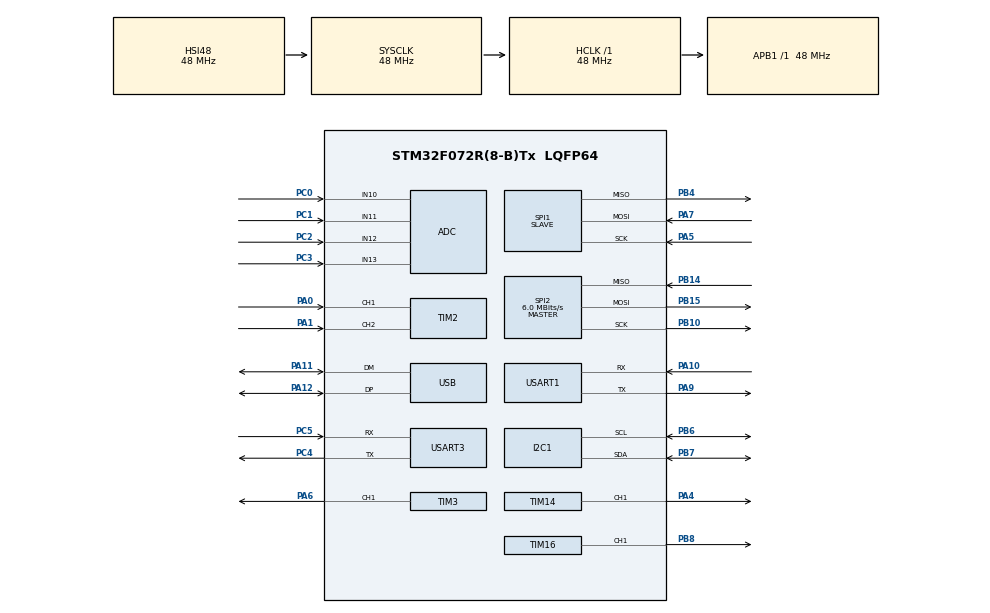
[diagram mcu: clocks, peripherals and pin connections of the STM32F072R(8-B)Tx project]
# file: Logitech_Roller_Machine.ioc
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Dma.I2C1_RX.4.Direction=DMA_PERIPH_TO_MEMORY
Dma.I2C1_RX.4.Instance=DMA1_Channel3
Dma.I2C1_RX.4.MemDataAlignment=DMA_MDATAALIGN_BYTE
Dma.I2C1_RX.4.MemInc=DMA_MINC_ENABLE
Dma.I2C1_RX.4.Mode=DMA_NORMAL
Dma.I2C1_RX.4.PeriphDataAlignment=DMA_PDATAALIGN_BYTE
Dma.I2C1_RX.4.PeriphInc=DMA_PINC_DISABLE
Dma.I2C1_RX.4.Priority=DMA_PRIORITY_LOW
Dma.I2C1_TX.5.Direction=DMA_MEMORY_TO_PERIPH
Dma.I2C1_TX.5.Instance=DMA1_Channel2
Dma.I2C1_TX.5.MemDataAlignment=DMA_MDATAALIGN_BYTE
Dma.I2C1_TX.5.MemInc=DMA_MINC_ENABLE
Dma.I2C1_TX.5.Mode=DMA_NORMAL
Dma.I2C1_TX.5.PeriphDataAlignment=DMA_PDATAALIGN_BYTE
Dma.I2C1_TX.5.PeriphInc=DMA_PINC_DISABLE
Dma.I2C1_TX.5.Priority=DMA_PRIORITY_LOW
Dma.Request0=USART3_RX
Dma.Request1=USART3_TX
Dma.Request2=USART1_RX
Dma.Request3=USART1_TX
Dma.Request4=I2C1_RX
Dma.Request5=I2C1_TX
Dma.USART1_RX.2.Direction=DMA_PERIPH_TO_MEMORY
Dma.USART1_RX.2.Instance=DMA1_Channel5
Dma.USART1_RX.2.MemDataAlignment=DMA_MDATAALIGN_BYTE
Dma.USART1_RX.2.MemInc=DMA_MINC_ENABLE
Dma.USART1_RX.2.Mode=DMA_NORMAL
Dma.USART1_RX.2.PeriphDataAlignment=DMA_PDATAALIGN_BYTE
Dma.USART1_RX.2.PeriphInc=DMA_PINC_DISABLE
Dma.USART1_RX.2.Priority=DMA_PRIORITY_LOW
Dma.USART1_TX.3.Direction=DMA_MEMORY_TO_PERIPH
Dma.USART1_TX.3.Instance=DMA1_Channel4
Dma.USART1_TX.3.MemDataAlignment=DMA_MDATAALIGN_BYTE
Dma.USART1_TX.3.MemInc=DMA_MINC_ENABLE
Dma.USART1_TX.3.Mode=DMA_NORMAL
Dma.USART1_TX.3.PeriphDataAlignment=DMA_PDATAALIGN_BYTE
Dma.USART1_TX.3.PeriphInc=DMA_PINC_DISABLE
Dma.USART1_TX.3.Priority=DMA_PRIORITY_LOW
Dma.USART3_RX.0.Direction=DMA_PERIPH_TO_MEMORY
Dma.USART3_RX.0.Instance=DMA1_Channel6
Dma.USART3_RX.0.MemDataAlignment=DMA_MDATAALIGN_BYTE
Dma.USART3_RX.0.MemInc=DMA_MINC_ENABLE
Dma.USART3_RX.0.Mode=DMA_NORMAL
Dma.USART3_RX.0.PeriphDataAlignment=DMA_PDATAALIGN_BYTE
Dma.USART3_RX.0.PeriphInc=DMA_PINC_DISABLE
Dma.USART3_RX.0.Priority=DMA_PRIORITY_LOW
Dma.USART3_TX.1.Direction=DMA_MEMORY_TO_PERIPH
Dma.USART3_TX.1.Instance=DMA1_Channel7
Dma.USART3_TX.1.MemDataAlignment=DMA_MDATAALIGN_BYTE
Dma.USART3_TX.1.MemInc=DMA_MINC_ENABLE
Dma.USART3_TX.1.Mode=DMA_NORMAL
Dma.USART3_TX.1.PeriphDataAlignment=DMA_PDATAALIGN_BYTE
Dma.USART3_TX.1.PeriphInc=DMA_PINC_DISABLE
Dma.USART3_TX.1.Priority=DMA_PRIORITY_LOW
Mcu.Family=STM32F0
Mcu.Name=STM32F072R(8-B)Tx
Mcu.Package=LQFP64
NVIC.DMA1_Channel2_3_IRQn=true\:0\:0\:false\:false\:true\:false\:true
NVIC.DMA1_Channel4_5_6_7_IRQn=true\:0\:0\:false\:false\:true\:false\:true
PA0.Signal=S_TIM2_CH1_ETR
PA1.Signal=S_TIM2_CH2
PA10.Mode=Asynchronous
PA10.Signal=USART1_RX
PA11.Mode=Device
PA11.Signal=USB_DM
PA12.Mode=Device
PA12.Signal=USB_DP
PA4.Signal=S_TIM14_CH1
PA5.Mode=Full_Duplex_Slave
PA5.Signal=SPI1_SCK
PA6.Signal=S_TIM3_CH1
PA7.Mode=Full_Duplex_Slave
PA7.Signal=SPI1_MOSI
PA9.Mode=Asynchronous
PA9.Signal=USART1_TX
PB10.Mode=Full_Duplex_Master
PB10.Signal=SPI2_SCK
PB14.Mode=Full_Duplex_Master
PB14.Signal=SPI2_MISO
PB15.Mode=Full_Duplex_Master
PB15.Signal=SPI2_MOSI
PB4.Mode=Full_Duplex_Slave
PB4.Signal=SPI1_MISO
PB6.Mode=I2C
PB6.Signal=I2C1_SCL
PB7.Mode=I2C
PB7.Signal=I2C1_SDA
PB8.Signal=S_TIM16_CH1
PC0.Mode=IN10
PC0.Signal=ADC_IN10
PC1.Mode=IN11
PC1.Signal=ADC_IN11
PC2.Mode=IN12
PC2.Signal=ADC_IN12
PC3.Mode=IN13
PC3.Signal=ADC_IN13
PC4.Mode=Asynchronous
PC4.Signal=USART3_TX
PC5.Mode=Asynchronous
PC5.Signal=USART3_RX
ProjectManager.HeapSize=0x200
ProjectManager.StackSize=0x400
ProjectManager.TargetToolchain=MDK-ARM V5
RCC.AHBFreq_Value=48000000
RCC.APB1Freq_Value=48000000
RCC.APB1TimFreq_Value=48000000
RCC.HCLKFreq_Value=48000000
RCC.SYSCLKFreq_VALUE=48000000
RCC.SYSCLKSource=RCC_SYSCLKSOURCE_HSI48
SH.S_TIM14_CH1.0=TIM14_CH1,PWM Generation1 CH1
SH.S_TIM16_CH1.0=TIM16_CH1,PWM Generation1 CH1
SH.S_TIM2_CH1_ETR.0=TIM2_CH1,Encoder_Interface
SH.S_TIM2_CH2.0=TIM2_CH2,Encoder_Interface
SH.S_TIM3_CH1.0=TIM3_CH1,PWM Generation1 CH1
SPI1.Direction=SPI_DIRECTION_2LINES
SPI1.Mode=SPI_MODE_SLAVE
SPI1.VirtualType=VM_SLAVE
SPI2.BaudRatePrescaler=SPI_BAUDRATEPRESCALER_8
SPI2.CalculateBaudRate=6.0 MBits/s
SPI2.Direction=SPI_DIRECTION_2LINES
SPI2.Mode=SPI_MODE_MASTER
SPI2.VirtualType=VM_MASTER
TIM14.Channel=TIM_CHANNEL_1
TIM16.Channel=TIM_CHANNEL_1
TIM3.Channel-PWM\ Generation1\ CH1=TIM_CHANNEL_1
USART1.VirtualMode-Asynchronous=VM_ASYNC
USART3.VirtualMode-Asynchronous=VM_ASYNC
VP_TIM14_VS_ClockSourceINT.Mode=Enable_Timer
VP_TIM16_VS_ClockSourceINT.Mode=Enable_Timer
VP_TIM16_VS_OPM.Mode=OPM_bit
board=custom

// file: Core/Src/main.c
/* USER CODE BEGIN Header */
/**
  ******************************************************************************
  * @file           : main.c
  * @brief          : Main program body
  ******************************************************************************
  * @attention
  *
  * <h2><center>&copy; Copyright (c) 2024 STMicroelectronics.
  * All rights reserved.</center></h2>
  *
  * This software component is licensed by ST under BSD 3-Clause license,
  * the "License"; You may not use this file except in compliance with the
  * License. You may obtain a copy of the License at:
  *                        opensource.org/licenses/BSD-3-Clause
  *
  ******************************************************************************
  */
/* USER CODE END Header */
#include "main.h"
#include "motor.h"
#include "uart.h"
#include "hmi.h"

ADC_HandleTypeDef hadc;

I2C_HandleTypeDef hi2c1;
DMA_HandleTypeDef hdma_i2c1_rx;
DMA_HandleTypeDef hdma_i2c1_tx;

SPI_HandleTypeDef hspi1;
SPI_HandleTypeDef hspi2;

TIM_HandleTypeDef htim2;
TIM_HandleTypeDef htim3;
TIM_HandleTypeDef htim14;
TIM_HandleTypeDef htim16;

UART_HandleTypeDef huart1;
UART_HandleTypeDef huart3;
DMA_HandleTypeDef hdma_usart1_rx;
DMA_HandleTypeDef hdma_usart1_tx;
DMA_HandleTypeDef hdma_usart3_rx;
DMA_HandleTypeDef hdma_usart3_tx;

PCD_HandleTypeDef hpcd_USB_FS;

/* USER CODE BEGIN PV */
GPIO_FUNCTION_STRUCT wheel_motor_enable = {GPIOB, GPIO_PIN_0};
GPIO_FUNCTION_STRUCT wheel_motor_direction = {GPIOB, GPIO_PIN_1};
DC_MOTOR wheel_motor = {&wheel_motor_enable, &wheel_motor_direction, TIM14, 1, 0, 0, MOTOR_IDLE, 0, 0, 0};

uint32_t new_tick = 0;
uint32_t lastTimeTick_wheel_motor_pid = 0;
uint32_t lastTimeTick_for_test = 0;

uint16_t Target = 1280;
uint16_t _last_Target = 1280;
uint16_t _Target = 0;
int16_t encoder_value = 0;
int32_t error = 0;
int32_t ierror = 0;

int page_index = 0;
/* USER CODE END PV */

void SystemClock_Config(void);
static void MX_GPIO_Init(void);
static void MX_DMA_Init(void);
static void MX_ADC_Init(void);
static void MX_I2C1_Init(void);
static void MX_TIM2_Init(void);
static void MX_TIM3_Init(void);
static void MX_TIM14_Init(void);
static void MX_TIM16_Init(void);
static void MX_USART1_UART_Init(void);
static void MX_USART3_UART_Init(void);
static void MX_SPI1_Init(void);
static void MX_SPI2_Init(void);
static void MX_USB_PCD_Init(void);
/* USER CODE BEGIN PFP */
_Bool isElapsedTimeNoReset(uint32_t _TimeInterval ,uint32_t _lastTimeTick);
void control_wheel_position(int32_t target, int32_t PV, double P_Gain, double I_Gain, double D_Gain);
/* USER CODE END PFP */

int main(void)
{

  /* MCU Configuration--------------------------------------------------------*/

  /* Reset of all peripherals, Initializes the Flash interface and the Systick. */
  HAL_Init();

  /* Configure the system clock */
  SystemClock_Config();

  /* Initialize all configured peripherals */
  MX_GPIO_Init();
  MX_DMA_Init();
  MX_ADC_Init();
  MX_I2C1_Init();
  MX_TIM2_Init();
  MX_TIM3_Init();
  MX_TIM14_Init();
  MX_TIM16_Init();
  MX_USART1_UART_Init();
  MX_USART3_UART_Init();
  MX_SPI1_Init();
  MX_SPI2_Init();
  MX_USB_PCD_Init();
  /* USER CODE BEGIN 2 */
	//init_dc_motor(&wheel_motor);
	MSG_InitializeQeueue();
	USART1_START_RX();
	USART3_START_RX();

	WritePage_to_HMI(PAGE_INIT);
	HAL_Delay(2000);
	WritePage_to_HMI(PAGE_MAIN);

	HAL_TIM_PWM_Start(&htim14, TIM_CHANNEL_1);
	HAL_TIM_Encoder_Start(&htim2, TIM_CHANNEL_ALL);
	HAL_Delay(500);
	run_motor_pwm(&wheel_motor, 0);
	lastTimeTick_for_test = new_tick;
  /* USER CODE END 2 */

  /* Infinite loop */
  while (1)
  {
		new_tick = HAL_GetTick();

		control_wheel_position(232, TIM2->CNT, 0.35, 0.002, 6);
		//Write_Parameters_To_HMI(VALUE_MOVEMENT, TIM2->CNT);
    HAL_Delay(1);
  }
}

void SystemClock_Config(void)
{
  RCC_OscInitTypeDef RCC_OscInitStruct = {0};
  RCC_ClkInitTypeDef RCC_ClkInitStruct = {0};
  RCC_PeriphCLKInitTypeDef PeriphClkInit = {0};

  /** Initializes the RCC Oscillators according to the specified parameters
  * in the RCC_OscInitTypeDef structure.
  */
  RCC_OscInitStruct.OscillatorType = RCC_OSCILLATORTYPE_HSI|RCC_OSCILLATORTYPE_HSI14
                              |RCC_OSCILLATORTYPE_HSI48;
  RCC_OscInitStruct.HSIState = RCC_HSI_ON;
  RCC_OscInitStruct.HSI48State = RCC_HSI48_ON;
  RCC_OscInitStruct.HSI14State = RCC_HSI14_ON;
  RCC_OscInitStruct.HSICalibrationValue = RCC_HSICALIBRATION_DEFAULT;
  RCC_OscInitStruct.HSI14CalibrationValue = 16;
  RCC_OscInitStruct.PLL.PLLState = RCC_PLL_NONE;
  if (HAL_RCC_OscConfig(&RCC_OscInitStruct) != HAL_OK)
  {
    Error_Handler();
  }
  /** Initializes the CPU, AHB and APB buses clocks
  */
  RCC_ClkInitStruct.ClockType = RCC_CLOCKTYPE_HCLK|RCC_CLOCKTYPE_SYSCLK
                              |RCC_CLOCKTYPE_PCLK1;
  RCC_ClkInitStruct.SYSCLKSource = RCC_SYSCLKSOURCE_HSI48;
  RCC_ClkInitStruct.AHBCLKDivider = RCC_SYSCLK_DIV1;
  RCC_ClkInitStruct.APB1CLKDivider = RCC_HCLK_DIV1;

  if (HAL_RCC_ClockConfig(&RCC_ClkInitStruct, FLASH_LATENCY_1) != HAL_OK)
  {
    Error_Handler();
  }
  PeriphClkInit.PeriphClockSelection = RCC_PERIPHCLK_USB|RCC_PERIPHCLK_USART1
                              |RCC_PERIPHCLK_I2C1;
  PeriphClkInit.Usart1ClockSelection = RCC_USART1CLKSOURCE_PCLK1;
  PeriphClkInit.I2c1ClockSelection = RCC_I2C1CLKSOURCE_HSI;
  PeriphClkInit.UsbClockSelection = RCC_USBCLKSOURCE_HSI48;

  if (HAL_RCCEx_PeriphCLKConfig(&PeriphClkInit) != HAL_OK)
  {
    Error_Handler();
  }
}

static void MX_ADC_Init(void)
{

  ADC_ChannelConfTypeDef sConfig = {0};

  /** Configure the global features of the ADC (Clock, Resolution, Data Alignment and number of conversion)
  */
  hadc.Instance = ADC1;
  hadc.Init.ClockPrescaler = ADC_CLOCK_ASYNC_DIV1;
  hadc.Init.Resolution = ADC_RESOLUTION_12B;
  hadc.Init.DataAlign = ADC_DATAALIGN_RIGHT;
  hadc.Init.ScanConvMode = ADC_SCAN_DIRECTION_FORWARD;
  hadc.Init.EOCSelection = ADC_EOC_SINGLE_CONV;
  hadc.Init.LowPowerAutoWait = DISABLE;
  hadc.Init.LowPowerAutoPowerOff = DISABLE;
  hadc.Init.ContinuousConvMode = DISABLE;
  hadc.Init.DiscontinuousConvMode = DISABLE;
  hadc.Init.ExternalTrigConv = ADC_SOFTWARE_START;
  hadc.Init.ExternalTrigConvEdge = ADC_EXTERNALTRIGCONVEDGE_NONE;
  hadc.Init.DMAContinuousRequests = DISABLE;
  hadc.Init.Overrun = ADC_OVR_DATA_PRESERVED;
  if (HAL_ADC_Init(&hadc) != HAL_OK)
  {
    Error_Handler();
  }
  /** Configure for the selected ADC regular channel to be converted.
  */
  sConfig.Channel = ADC_CHANNEL_10;
  sConfig.Rank = ADC_RANK_CHANNEL_NUMBER;
  sConfig.SamplingTime = ADC_SAMPLETIME_1CYCLE_5;
  if (HAL_ADC_ConfigChannel(&hadc, &sConfig) != HAL_OK)
  {
    Error_Handler();
  }
  /** Configure for the selected ADC regular channel to be converted.
  */
  sConfig.Channel = ADC_CHANNEL_11;
  if (HAL_ADC_ConfigChannel(&hadc, &sConfig) != HAL_OK)
  {
    Error_Handler();
  }
  /** Configure for the selected ADC regular channel to be converted.
  */
  sConfig.Channel = ADC_CHANNEL_12;
  if (HAL_ADC_ConfigChannel(&hadc, &sConfig) != HAL_OK)
  {
    Error_Handler();
  }
  /** Configure for the selected ADC regular channel to be converted.
  */
  sConfig.Channel = ADC_CHANNEL_13;
  if (HAL_ADC_ConfigChannel(&hadc, &sConfig) != HAL_OK)
  {
    Error_Handler();
  }

}

static void MX_I2C1_Init(void)
{

  hi2c1.Instance = I2C1;
  hi2c1.Init.Timing = 0x2000090E;
  hi2c1.Init.OwnAddress1 = 0;
  hi2c1.Init.AddressingMode = I2C_ADDRESSINGMODE_7BIT;
  hi2c1.Init.DualAddressMode = I2C_DUALADDRESS_DISABLE;
  hi2c1.Init.OwnAddress2 = 0;
  hi2c1.Init.OwnAddress2Masks = I2C_OA2_NOMASK;
  hi2c1.Init.GeneralCallMode = I2C_GENERALCALL_DISABLE;
  hi2c1.Init.NoStretchMode = I2C_NOSTRETCH_DISABLE;
  if (HAL_I2C_Init(&hi2c1) != HAL_OK)
  {
    Error_Handler();
  }
  /** Configure Analogue filter
  */
  if (HAL_I2CEx_ConfigAnalogFilter(&hi2c1, I2C_ANALOGFILTER_ENABLE) != HAL_OK)
  {
    Error_Handler();
  }
  /** Configure Digital filter
  */
  if (HAL_I2CEx_ConfigDigitalFilter(&hi2c1, 0) != HAL_OK)
  {
    Error_Handler();
  }

}

static void MX_SPI1_Init(void)
{

  /* SPI1 parameter configuration*/
  hspi1.Instance = SPI1;
  hspi1.Init.Mode = SPI_MODE_SLAVE;
  hspi1.Init.Direction = SPI_DIRECTION_2LINES;
  hspi1.Init.DataSize = SPI_DATASIZE_4BIT;
  hspi1.Init.CLKPolarity = SPI_POLARITY_LOW;
  hspi1.Init.CLKPhase = SPI_PHASE_1EDGE;
  hspi1.Init.NSS = SPI_NSS_SOFT;
  hspi1.Init.FirstBit = SPI_FIRSTBIT_MSB;
  hspi1.Init.TIMode = SPI_TIMODE_DISABLE;
  hspi1.Init.CRCCalculation = SPI_CRCCALCULATION_DISABLE;
  hspi1.Init.CRCPolynomial = 7;
  hspi1.Init.CRCLength = SPI_CRC_LENGTH_DATASIZE;
  hspi1.Init.NSSPMode = SPI_NSS_PULSE_DISABLE;
  if (HAL_SPI_Init(&hspi1) != HAL_OK)
  {
    Error_Handler();
  }

}

static void MX_SPI2_Init(void)
{

  /* SPI2 parameter configuration*/
  hspi2.Instance = SPI2;
  hspi2.Init.Mode = SPI_MODE_MASTER;
  hspi2.Init.Direction = SPI_DIRECTION_2LINES;
  hspi2.Init.DataSize = SPI_DATASIZE_4BIT;
  hspi2.Init.CLKPolarity = SPI_POLARITY_LOW;
  hspi2.Init.CLKPhase = SPI_PHASE_1EDGE;
  hspi2.Init.NSS = SPI_NSS_SOFT;
  hspi2.Init.BaudRatePrescaler = SPI_BAUDRATEPRESCALER_8;
  hspi2.Init.FirstBit = SPI_FIRSTBIT_MSB;
  hspi2.Init.TIMode = SPI_TIMODE_DISABLE;
  hspi2.Init.CRCCalculation = SPI_CRCCALCULATION_DISABLE;
  hspi2.Init.CRCPolynomial = 7;
  hspi2.Init.CRCLength = SPI_CRC_LENGTH_DATASIZE;
  hspi2.Init.NSSPMode = SPI_NSS_PULSE_ENABLE;
  if (HAL_SPI_Init(&hspi2) != HAL_OK)
  {
    Error_Handler();
  }

}

static void MX_TIM2_Init(void)
{

  TIM_Encoder_InitTypeDef sConfig = {0};
  TIM_MasterConfigTypeDef sMasterConfig = {0};

  htim2.Instance = TIM2;
  htim2.Init.Prescaler = 0;
  htim2.Init.CounterMode = TIM_COUNTERMODE_UP;
  htim2.Init.Period = 4294967295;
  htim2.Init.ClockDivision = TIM_CLOCKDIVISION_DIV1;
  htim2.Init.AutoReloadPreload = TIM_AUTORELOAD_PRELOAD_DISABLE;
  sConfig.EncoderMode = TIM_ENCODERMODE_TI12;
  sConfig.IC1Polarity = TIM_ICPOLARITY_RISING;
  sConfig.IC1Selection = TIM_ICSELECTION_DIRECTTI;
  sConfig.IC1Prescaler = TIM_ICPSC_DIV1;
  sConfig.IC1Filter = 0;
  sConfig.IC2Polarity = TIM_ICPOLARITY_RISING;
  sConfig.IC2Selection = TIM_ICSELECTION_DIRECTTI;
  sConfig.IC2Prescaler = TIM_ICPSC_DIV1;
  sConfig.IC2Filter = 0;
  if (HAL_TIM_Encoder_Init(&htim2, &sConfig) != HAL_OK)
  {
    Error_Handler();
  }
  sMasterConfig.MasterOutputTrigger = TIM_TRGO_RESET;
  sMasterConfig.MasterSlaveMode = TIM_MASTERSLAVEMODE_DISABLE;
  if (HAL_TIMEx_MasterConfigSynchronization(&htim2, &sMasterConfig) != HAL_OK)
  {
    Error_Handler();
  }

}

static void MX_TIM3_Init(void)
{

  TIM_MasterConfigTypeDef sMasterConfig = {0};
  TIM_OC_InitTypeDef sConfigOC = {0};

  htim3.Instance = TIM3;
  htim3.Init.Prescaler = 0;
  htim3.Init.CounterMode = TIM_COUNTERMODE_UP;
  htim3.Init.Period = 65535;
  htim3.Init.ClockDivision = TIM_CLOCKDIVISION_DIV1;
  htim3.Init.AutoReloadPreload = TIM_AUTORELOAD_PRELOAD_DISABLE;
  if (HAL_TIM_PWM_Init(&htim3) != HAL_OK)
  {
    Error_Handler();
  }
  sMasterConfig.MasterOutputTrigger = TIM_TRGO_RESET;
  sMasterConfig.MasterSlaveMode = TIM_MASTERSLAVEMODE_DISABLE;
  if (HAL_TIMEx_MasterConfigSynchronization(&htim3, &sMasterConfig) != HAL_OK)
  {
    Error_Handler();
  }
  sConfigOC.OCMode = TIM_OCMODE_PWM1;
  sConfigOC.Pulse = 0;
  sConfigOC.OCPolarity = TIM_OCPOLARITY_HIGH;
  sConfigOC.OCFastMode = TIM_OCFAST_DISABLE;
  if (HAL_TIM_PWM_ConfigChannel(&htim3, &sConfigOC, TIM_CHANNEL_1) != HAL_OK)
  {
    Error_Handler();
  }
  HAL_TIM_MspPostInit(&htim3);

}

static void MX_TIM14_Init(void)
{

  TIM_OC_InitTypeDef sConfigOC = {0};

  htim14.Instance = TIM14;
  htim14.Init.Prescaler = 0;
  htim14.Init.CounterMode = TIM_COUNTERMODE_UP;
  htim14.Init.Period = 65535;
  htim14.Init.ClockDivision = TIM_CLOCKDIVISION_DIV1;
  htim14.Init.AutoReloadPreload = TIM_AUTORELOAD_PRELOAD_DISABLE;
  if (HAL_TIM_Base_Init(&htim14) != HAL_OK)
  {
    Error_Handler();
  }
  if (HAL_TIM_PWM_Init(&htim14) != HAL_OK)
  {
    Error_Handler();
  }
  sConfigOC.OCMode = TIM_OCMODE_PWM1;
  sConfigOC.Pulse = 0;
  sConfigOC.OCPolarity = TIM_OCPOLARITY_HIGH;
  sConfigOC.OCFastMode = TIM_OCFAST_DISABLE;
  if (HAL_TIM_PWM_ConfigChannel(&htim14, &sConfigOC, TIM_CHANNEL_1) != HAL_OK)
  {
    Error_Handler();
  }
  HAL_TIM_MspPostInit(&htim14);

}

static void MX_TIM16_Init(void)
{

  TIM_OC_InitTypeDef sConfigOC = {0};
  TIM_BreakDeadTimeConfigTypeDef sBreakDeadTimeConfig = {0};

  htim16.Instance = TIM16;
  htim16.Init.Prescaler = 0;
  htim16.Init.CounterMode = TIM_COUNTERMODE_UP;
  htim16.Init.Period = 65535;
  htim16.Init.ClockDivision = TIM_CLOCKDIVISION_DIV1;
  htim16.Init.RepetitionCounter = 0;
  htim16.Init.AutoReloadPreload = TIM_AUTORELOAD_PRELOAD_DISABLE;
  if (HAL_TIM_Base_Init(&htim16) != HAL_OK)
  {
    Error_Handler();
  }
  if (HAL_TIM_PWM_Init(&htim16) != HAL_OK)
  {
    Error_Handler();
  }
  if (HAL_TIM_OnePulse_Init(&htim16, TIM_OPMODE_SINGLE) != HAL_OK)
  {
    Error_Handler();
  }
  sConfigOC.OCMode = TIM_OCMODE_PWM1;
  sConfigOC.Pulse = 0;
  sConfigOC.OCPolarity = TIM_OCPOLARITY_HIGH;
  sConfigOC.OCNPolarity = TIM_OCNPOLARITY_HIGH;
  sConfigOC.OCFastMode = TIM_OCFAST_DISABLE;
  sConfigOC.OCIdleState = TIM_OCIDLESTATE_RESET;
  sConfigOC.OCNIdleState = TIM_OCNIDLESTATE_RESET;
  if (HAL_TIM_PWM_ConfigChannel(&htim16, &sConfigOC, TIM_CHANNEL_1) != HAL_OK)
  {
    Error_Handler();
  }
  sBreakDeadTimeConfig.OffStateRunMode = TIM_OSSR_DISABLE;
  sBreakDeadTimeConfig.OffStateIDLEMode = TIM_OSSI_DISABLE;
  sBreakDeadTimeConfig.LockLevel = TIM_LOCKLEVEL_OFF;
  sBreakDeadTimeConfig.DeadTime = 0;
  sBreakDeadTimeConfig.BreakState = TIM_BREAK_DISABLE;
  sBreakDeadTimeConfig.BreakPolarity = TIM_BREAKPOLARITY_HIGH;
  sBreakDeadTimeConfig.AutomaticOutput = TIM_AUTOMATICOUTPUT_DISABLE;
  if (HAL_TIMEx_ConfigBreakDeadTime(&htim16, &sBreakDeadTimeConfig) != HAL_OK)
  {
    Error_Handler();
  }
  HAL_TIM_MspPostInit(&htim16);

}

static void MX_USART1_UART_Init(void)
{

  huart1.Instance = USART1;
  huart1.Init.BaudRate = 9600;
  huart1.Init.WordLength = UART_WORDLENGTH_8B;
  huart1.Init.StopBits = UART_STOPBITS_1;
  huart1.Init.Parity = UART_PARITY_NONE;
  huart1.Init.Mode = UART_MODE_TX_RX;
  huart1.Init.HwFlowCtl = UART_HWCONTROL_NONE;
  huart1.Init.OverSampling = UART_OVERSAMPLING_16;
  huart1.Init.OneBitSampling = UART_ONE_BIT_SAMPLE_DISABLE;
  huart1.AdvancedInit.AdvFeatureInit = UART_ADVFEATURE_NO_INIT;
  if (HAL_UART_Init(&huart1) != HAL_OK)
  {
    Error_Handler();
  }
  /* USER CODE BEGIN USART1_Init 2 */
	HAL_NVIC_SetPriority(USART1_IRQn, 0, 0);
	HAL_NVIC_EnableIRQ(USART1_IRQn);
  /* USER CODE END USART1_Init 2 */

}

static void MX_USART3_UART_Init(void)
{

  huart3.Instance = USART3;
  huart3.Init.BaudRate = 38400;
  huart3.Init.WordLength = UART_WORDLENGTH_8B;
  huart3.Init.StopBits = UART_STOPBITS_1;
  huart3.Init.Parity = UART_PARITY_NONE;
  huart3.Init.Mode = UART_MODE_TX_RX;
  huart3.Init.HwFlowCtl = UART_HWCONTROL_NONE;
  huart3.Init.OverSampling = UART_OVERSAMPLING_16;
  huart3.Init.OneBitSampling = UART_ONE_BIT_SAMPLE_DISABLE;
  huart3.AdvancedInit.AdvFeatureInit = UART_ADVFEATURE_NO_INIT;
  if (HAL_UART_Init(&huart3) != HAL_OK)
  {
    Error_Handler();
  }

}

static void MX_USB_PCD_Init(void)
{

  hpcd_USB_FS.Instance = USB;
  hpcd_USB_FS.Init.dev_endpoints = 8;
  hpcd_USB_FS.Init.speed = PCD_SPEED_FULL;
  hpcd_USB_FS.Init.phy_itface = PCD_PHY_EMBEDDED;
  hpcd_USB_FS.Init.low_power_enable = DISABLE;
  hpcd_USB_FS.Init.lpm_enable = DISABLE;
  hpcd_USB_FS.Init.battery_charging_enable = DISABLE;
  if (HAL_PCD_Init(&hpcd_USB_FS) != HAL_OK)
  {
    Error_Handler();
  }

}

static void MX_DMA_Init(void)
{

  /* DMA controller clock enable */
  __HAL_RCC_DMA1_CLK_ENABLE();

  /* DMA interrupt init */
  /* DMA1_Channel2_3_IRQn interrupt configuration */
  HAL_NVIC_SetPriority(DMA1_Channel2_3_IRQn, 0, 0);
  HAL_NVIC_EnableIRQ(DMA1_Channel2_3_IRQn);
  /* DMA1_Channel4_5_6_7_IRQn interrupt configuration */
  HAL_NVIC_SetPriority(DMA1_Channel4_5_6_7_IRQn, 0, 0);
  HAL_NVIC_EnableIRQ(DMA1_Channel4_5_6_7_IRQn);

}

static void MX_GPIO_Init(void)
{
  GPIO_InitTypeDef GPIO_InitStruct = {0};

  /* GPIO Ports Clock Enable */
	__HAL_RCC_GPIOA_CLK_ENABLE();
	__HAL_RCC_GPIOC_CLK_ENABLE();
  __HAL_RCC_GPIOF_CLK_ENABLE();
  __HAL_RCC_GPIOB_CLK_ENABLE();
	__HAL_RCC_GPIOD_CLK_ENABLE();

	GPIO_InitStruct.Pin = GPIO_PIN_0|GPIO_PIN_1;
	GPIO_InitStruct.Mode = GPIO_MODE_OUTPUT_PP;
	GPIO_InitStruct.Pull = GPIO_PULLDOWN;
	HAL_GPIO_Init(GPIOB, &GPIO_InitStruct);
}

/* USER CODE BEGIN 4 */
_Bool isElapsedTime(uint32_t _TimeInterval ,uint32_t* _lastTimeTick)
{
	uint32_t _elapsedTick = 0;
	if(*_lastTimeTick > new_tick)
	{
		_elapsedTick = (uint32_t)(4294967295 - *_lastTimeTick + new_tick);
	}
	else
	{
		_elapsedTick = (uint32_t)(new_tick - *_lastTimeTick);
	}

	if(_elapsedTick >= _TimeInterval)
	{
		*_lastTimeTick = new_tick;
		return 1;
	}
	else
	{
		return 0;
	}
}

_Bool isElapsedTimeNoReset(uint32_t _TimeInterval ,uint32_t _lastTimeTick)
{
	uint32_t _elapsedTick = 0;
	if(_lastTimeTick > new_tick)
	{
		_elapsedTick = (uint32_t)(4294967295 - _lastTimeTick + new_tick);
	}
	else
	{
		_elapsedTick = (uint32_t)(new_tick - _lastTimeTick);
	}

	if(_elapsedTick >= _TimeInterval)
	{
		return 1;
	}
	else
	{
		return 0;
	}
}

int8_t PID(int32_t target, int32_t PV, double P_Gain, double I_Gain, double D_Gain)
{
	/*if(target != _Target)
	{
		_Target = target;
		error = 0;
		ierror = 0;
	}*/
	int32_t output = (int32_t)(((double)(target - PV) * P_Gain) + ((double)((target-PV)-error) * D_Gain) + ((double)(ierror * I_Gain)));
	error = target - PV;
	ierror += error;
	if(output < 0)
	{
		if(output < -100)
		{
			output = -100;
		}
	}
	else
	{
		if(output > 100)
		{
			output = 100;
		}
	}
	return (int8_t)output;
}

void control_wheel_position(int32_t target, int32_t PV, double P_Gain, double I_Gain, double D_Gain)
{
	//HAL_GPIO_WritePin(Motor_Enable_Pin.Group, Motor_Enable_Pin.Pin, GPIO_PIN_SET);
	HAL_GPIO_WritePin(wheel_motor_enable.Group, wheel_motor_enable.Pin, GPIO_PIN_SET);
	int8_t speed = 0;
	if(isElapsedTime(5, &lastTimeTick_wheel_motor_pid))
	{
		speed = PID(target, PV, P_Gain, I_Gain, D_Gain);

		if(speed >= 0)
		{
			//speed = 100 - speed;
			HAL_GPIO_WritePin(wheel_motor_direction.Group, wheel_motor_direction.Pin, GPIO_PIN_SET);
		}
		else
		{
			speed *= -1;
			HAL_GPIO_WritePin(wheel_motor_direction.Group, wheel_motor_direction.Pin, GPIO_PIN_RESET);
		}

		if(speed < 9)
		{
			//speed = 0;
			//HAL_GPIO_WritePin(wheel_motor_enable.Group, wheel_motor_enable.Pin, GPIO_PIN_RESET);
		}
		run_motor_pwm(&wheel_motor, (((double)speed))/100.0);
	}
}

void control_wheel_velocity(int32_t velocity, double P_Gain, double I_Gain, double D_Gain)
{

	//control_wheel_position()
}

/* USER CODE END 4 */

void Error_Handler(void)
{
  __disable_irq();
  while (1)
  {
  }
}

/************************ (C) COPYRIGHT STMicroelectronics *****END OF FILE****/
